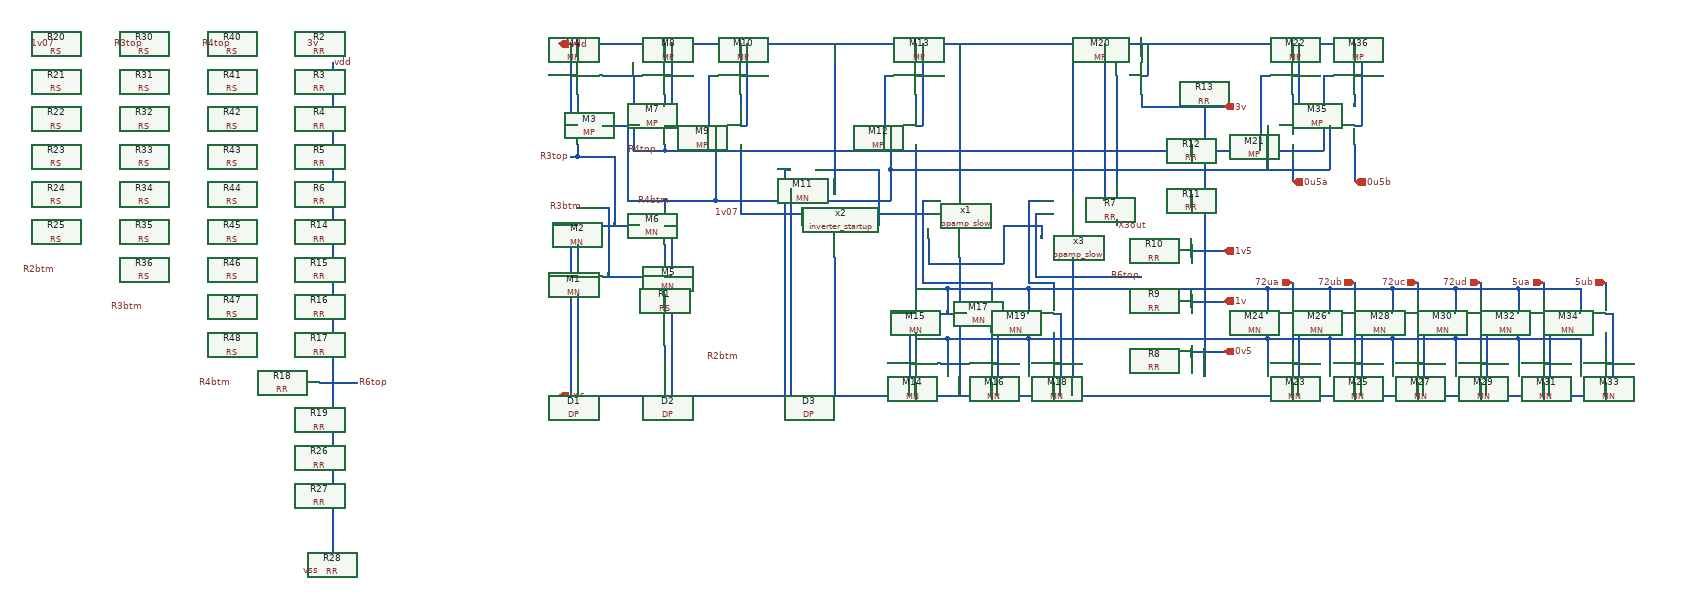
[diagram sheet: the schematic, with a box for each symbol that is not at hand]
v {xschem version=3.4.8RC file_version=1.3}
G {}
K {}
V {}
S {}
F {}
E {}
N 150 400 150 420 {lab=#net1}
N 50 370 110 370 {lab=R3btm}
N 50 290 110 290 {lab=R3top}
N 10 320 10 340 {lab=#net2}
N 150 320 150 340 {lab=#net3}
N 0 290 10 290 {lab=vss}
N 0 370 10 370 {lab=vss}
N 150 290 160 290 {lab=vss}
N 150 370 160 370 {lab=vss}
N 10 80 10 100 {lab=#net4}
N 150 80 150 100 {lab=#net5}
N 50 130 110 130 {lab=R4btm}
N 50 50 110 50 {lab=R4top}
N 0 50 10 50 {lab=vdd}
N 10 0 10 20 {lab=vdd}
N 150 0 150 20 {lab=vdd}
N 0 130 10 130 {lab=vdd}
N 150 130 160 130 {lab=vdd}
N 150 50 160 50 {lab=vdd}
N 100 50 100 170 {lab=R4top}
N 0 0 0 130 {lab=vdd}
N 160 0 160 130 {lab=vdd}
N 150 480 150 500 {lab=#net6}
N 0 290 0 560 {lab=vss}
N 10 400 10 500 {lab=#net7}
N 160 290 160 560 {lab=vss}
N 90 130 90 250 {lab=R4btm}
N 270 80 270 100 {lab=#net8}
N 270 0 270 20 {lab=vdd}
N 270 130 280 130 {lab=vdd}
N 270 50 280 50 {lab=vdd}
N 280 0 280 130 {lab=vdd}
N 220 50 220 170 {lab=R4top}
N 230 130 230 250 {lab=R4btm}
N 350 230 350 560 {lab=vss}
N 340 200 350 200 {lab=vss}
N 340 200 340 560 {lab=vss}
N 420 340 420 560 {lab=vss}
N 390 200 490 200 {lab=#net9}
N 490 200 490 290 {lab=#net9}
N 420 0 420 240 {lab=vdd}
N 550 80 550 100 {lab=#net10}
N 550 0 550 20 {lab=vdd}
N 550 130 560 130 {lab=vdd}
N 550 50 560 50 {lab=vdd}
N 560 0 560 130 {lab=vdd}
N 500 50 500 170 {lab=R4top}
N 540 430 550 430 {lab=vss}
N 540 510 550 510 {lab=vss}
N 550 460 550 480 {lab=#net11}
N 550 540 550 560 {lab=vss}
N 540 430 540 560 {lab=vss}
N 550 160 550 400 {lab=#net12}
N 670 430 680 430 {lab=vss}
N 670 510 680 510 {lab=vss}
N 670 460 670 480 {lab=#net13}
N 670 540 670 560 {lab=vss}
N 680 430 680 560 {lab=vss}
N 590 430 630 430 {lab=#net12}
N 590 510 630 510 {lab=#net11}
N 600 470 600 510 {lab=#net11}
N 600 390 600 430 {lab=#net12}
N 570 310 570 350 {lab=#net14}
N 690 290 690 350 {lab=#net14}
N 570 350 690 350 {lab=#net14}
N 620 340 620 560 {lab=vss}
N 620 0 620 240 {lab=vdd}
N 500 270 570 270 {lab=1v07}
N 560 250 570 250 {lab=#net15}
N 560 250 560 380 {lab=#net15}
N 560 380 670 380 {lab=#net15}
N 670 380 670 400 {lab=#net15}
N 270 270 500 270 {lab=1v07}
N 550 390 600 390 {lab=#net12}
N 550 470 600 470 {lab=#net11}
N 770 430 780 430 {lab=vss}
N 770 510 780 510 {lab=vss}
N 770 460 770 480 {lab=#net16}
N 770 540 770 560 {lab=vss}
N 780 430 780 560 {lab=vss}
N 770 380 770 400 {lab=#net17}
N 600 390 730 390 {lab=#net12}
N 730 390 730 430 {lab=#net12}
N 600 470 730 470 {lab=#net11}
N 730 470 730 510 {lab=#net11}
N 800 340 800 560 {lab=vss}
N 800 0 800 240 {lab=vdd}
N 690 290 750 290 {lab=#net14}
N 750 290 750 310 {lab=#net14}
N 730 250 750 250 {lab=#net17}
N 730 250 730 380 {lab=#net17}
N 730 380 770 380 {lab=#net17}
N 870 280 870 290 {lab=X3out}
N 740 270 750 270 {lab=R6top}
N 740 270 740 370 {lab=R6top}
N 910 50 920 50 {lab=vdd}
N 740 370 910 370 {lab=R6top}
N 1150 80 1150 100 {lab=#net18}
N 1150 0 1150 20 {lab=vdd}
N 1150 130 1160 130 {lab=vdd}
N 1150 50 1160 50 {lab=vdd}
N 1160 0 1160 130 {lab=vdd}
N 910 0 910 20 {lab=vdd}
N 870 50 870 220 {lab=#net19}
N 920 0 920 50 {lab=vdd}
N 910 100 990 100 {lab=3v}
N 990 160 990 180 {lab=#net20}
N 990 240 990 260 {lab=#net21}
N 990 320 990 340 {lab=1v5}
N 990 400 990 420 {lab=1v}
N 990 480 990 500 {lab=0v5}
N 1100 50 1100 170 {lab=R4top}
N 1110 130 1110 200 {lab=R4btm}
N 1150 430 1160 430 {lab=vss}
N 1150 510 1160 510 {lab=vss}
N 1150 460 1150 480 {lab=#net22}
N 1150 540 1150 560 {lab=vss}
N 1160 430 1160 560 {lab=vss}
N 1150 380 1150 400 {lab=72ua}
N 1110 390 1110 430 {lab=#net12}
N 1110 470 1110 510 {lab=#net11}
N 220 50 230 50 {lab=R4top}
N 500 50 510 50 {lab=R4top}
N 1100 50 1110 50 {lab=R4top}
N 1250 430 1260 430 {lab=vss}
N 1250 510 1260 510 {lab=vss}
N 1250 460 1250 480 {lab=#net23}
N 1250 540 1250 560 {lab=vss}
N 1260 430 1260 560 {lab=vss}
N 1250 380 1250 400 {lab=72ub}
N 1110 390 1210 390 {lab=#net12}
N 1210 390 1210 430 {lab=#net12}
N 1110 470 1210 470 {lab=#net11}
N 1210 470 1210 510 {lab=#net11}
N 1350 430 1360 430 {lab=vss}
N 1350 510 1360 510 {lab=vss}
N 1350 460 1350 480 {lab=#net24}
N 1350 540 1350 560 {lab=vss}
N 1360 430 1360 560 {lab=vss}
N 1350 380 1350 400 {lab=72uc}
N 1210 390 1310 390 {lab=#net12}
N 1310 390 1310 430 {lab=#net12}
N 1210 470 1310 470 {lab=#net11}
N 1310 470 1310 510 {lab=#net11}
N 1450 430 1460 430 {lab=vss}
N 1450 510 1460 510 {lab=vss}
N 1450 460 1450 480 {lab=#net25}
N 1450 540 1450 560 {lab=vss}
N 1460 430 1460 560 {lab=vss}
N 1450 380 1450 400 {lab=72ud}
N 1310 390 1410 390 {lab=#net12}
N 1410 390 1410 430 {lab=#net12}
N 1310 470 1410 470 {lab=#net11}
N 1410 470 1410 510 {lab=#net11}
N 1550 430 1560 430 {lab=vss}
N 1550 510 1560 510 {lab=vss}
N 1550 460 1550 480 {lab=#net26}
N 1550 540 1550 560 {lab=vss}
N 1560 430 1560 560 {lab=vss}
N 1550 380 1550 400 {lab=5ua}
N 1410 390 1510 390 {lab=#net12}
N 1510 390 1510 430 {lab=#net12}
N 1410 470 1510 470 {lab=#net11}
N 1510 470 1510 510 {lab=#net11}
N 1650 430 1660 430 {lab=vss}
N 1650 510 1660 510 {lab=vss}
N 1650 460 1650 480 {lab=#net27}
N 1650 540 1650 560 {lab=vss}
N 1660 430 1660 560 {lab=vss}
N 1650 380 1650 400 {lab=5ub}
N 1510 390 1610 390 {lab=#net12}
N 1610 390 1610 430 {lab=#net12}
N 1510 470 1610 470 {lab=#net11}
N 1610 470 1610 510 {lab=#net11}
N 1150 160 1150 220 {lab=0u5a}
N 1250 80 1250 100 {lab=#net28}
N 1250 0 1250 20 {lab=vdd}
N 1250 130 1260 130 {lab=vdd}
N 1250 50 1260 50 {lab=vdd}
N 1260 0 1260 130 {lab=vdd}
N 1200 50 1200 170 {lab=R4top}
N 1210 130 1210 200 {lab=R4btm}
N 1200 50 1210 50 {lab=R4top}
N 1250 160 1250 220 {lab=0u5b}
N 510 130 510 200 {lab=R4btm}
N 510 200 510 250 {lab=R4btm}
N 990 100 1040 100 {lab=3v}
N 990 330 1040 330 {lab=1v5}
N 990 410 1040 410 {lab=1v}
N 990 490 1040 490 {lab=0v5}
N -20 0 1260 -0 {lab=vdd}
N 100 170 150 170 {lab=R4top}
N 150 170 1200 170 {lab=R4top}
N 90 250 150 250 {lab=R4btm}
N 150 250 230 250 {lab=R4btm}
N 510 200 1210 200 {lab=R4btm}
N 230 250 510 250 {lab=R4btm}
N -20 560 1660 560 {lab=vss}
N 730 390 1110 390 {lab=#net12}
N 730 470 1110 470 {lab=#net11}
N 10 160 10 180 {lab=R3top}
N 70 180 70 290 {lab=R3top}
N 150 160 150 170 {lab=R4top}
N 10 260 60 260 {lab=R3btm}
N 60 260 60 370 {lab=R3btm}
N 150 250 150 260 {lab=R4btm}
N 370 270 370 290 {lab=1v07}
N 270 160 270 270 {lab=1v07}
N 10 180 70 180 {lab=R3top}
N 0 180 10 180 {lab=R3top}
N 850 0 850 250 {lab=vdd}
N 1010 100 1010 530 {lab=3v}
N -400 540 -340 540 {lab=R6top}
N -380 30 -380 810 {lab=vdd}
N 910 80 910 100 {lab=3v}
C {MN.sym} 50 370 0 1 {name=M1 model=NMOS w=10u l=2u nrd=0 nrs=0 m=5 spiceprefix=X}
C {MN.sym} 50 290 0 1 {name=M2 model=NMOS w=20u l=1u nrd=0 nrs=0 m=5 spiceprefix=X}
C {MN.sym} 110 370 0 0 {name=M5 model=NMOS w=10u l=2u nrd=0 nrs=0 m=5 spiceprefix=X}
C {MN.sym} 110 290 0 0 {name=M6 model=NMOS w=20u l=1u nrd=0 nrs=0 m=5 spiceprefix=X}
C {RS.sym} -680 0 0 0 {name=R30
w=4e-6
R=1
l=50e-6
model=F_RS
spiceprefix=X
tc1=0
tc2=0}
C {MP.sym} 50 130 0 1 {name=M3 model=PMOS w=20u l=1u nrd=0 nrs=0 m=5 spiceprefix=X}
C {MP.sym} 50 50 0 1 {name=M4 model=PMOS w=25u l=2u nrd=0 nrs=0 m=5 spiceprefix=X}
C {MP.sym} 110 130 0 0 {name=M7 model=PMOS w=20u l=1u nrd=0 nrs=0 m=5 spiceprefix=X}
C {MP.sym} 110 50 0 0 {name=M8 model=PMOS w=25u l=2u nrd=0 nrs=0 m=5 spiceprefix=X}
C {RS.sym} 150 420 0 0 {name=R1
w=4e-6
R=1
l=40.0e-6
model=F_RS
spiceprefix=X
tc1=0
tc2=0}
C {MP.sym} 230 130 0 0 {name=M9 model=PMOS w=20u l=1u nrd=0 nrs=0 m=5 spiceprefix=X}
C {MP.sym} 230 50 0 0 {name=M10 model=PMOS w=25u l=2u nrd=0 nrs=0 m=5 spiceprefix=X}
C {MN.sym} 390 200 0 1 {name=M11 model=NMOS w=10u l=2u nrd=0 nrs=0 m=3 spiceprefix=X}
C {inverter_startup.sym} 390 290 0 0 {name=x2}
C {MP.sym} 510 130 0 0 {name=M12 model=PMOS w=20u l=1u nrd=0 nrs=0 m=5 spiceprefix=X}
C {MP.sym} 510 50 0 0 {name=M13 model=PMOS w=25u l=2u nrd=0 nrs=0 m=5 spiceprefix=X}
C {MN.sym} 590 510 0 1 {name=M14 model=NMOS w=10u l=2u nrd=0 nrs=0 m=5 spiceprefix=X}
C {MN.sym} 590 430 0 1 {name=M15 model=NMOS w=20u l=1u nrd=0 nrs=0 m=5 spiceprefix=X}
C {MN.sym} 630 510 0 0 {name=M16 model=NMOS w=7u l=2u nrd=0 nrs=0 m=1 spiceprefix=X}
C {MN.sym} 630 430 0 0 {name=M17 model=NMOS w=15u l=1u nrd=0 nrs=0 m=1 spiceprefix=X}
C {opamp_slow.sym} 590 290 0 0 {name=x1}
C {MN.sym} 730 510 0 0 {name=M18 model=NMOS w=7u l=2u nrd=0 nrs=0 m=1 spiceprefix=X}
C {MN.sym} 730 430 0 0 {name=M19 model=NMOS w=15u l=1u nrd=0 nrs=0 m=1 spiceprefix=X}
C {opamp_slow.sym} 770 290 0 0 {name=x3}
C {MP.sym} 870 50 0 0 {name=M20 model=PMOS w=20u l=1u nrd=0 nrs=0 m=5 spiceprefix=X}
C {RR.sym} 870 280 2 0 {name=R7
w=2.8e-06
R=1
l=30.0e-06
model=F_RR
spiceprefix=X
tc1=0
tc2=0}
C {MP.sym} 1110 130 0 0 {name=M21 model=PMOS w=4u l=2u nrd=0 nrs=0 m=1 spiceprefix=X}
C {MP.sym} 1110 50 0 0 {name=M22 model=PMOS w=5u l=4u nrd=0 nrs=0 m=1 spiceprefix=X}
C {RR.sym} 990 500 0 0 {name=R8
w=2.8e-06
R=1
l=50.0e-06
model=F_RR
spiceprefix=X
tc1=0
tc2=0}
C {RR.sym} 990 340 0 0 {name=R10
w=2.8e-06
R=1
l=50.0e-06
model=F_RR
spiceprefix=X
tc1=0
tc2=0}
C {RR.sym} 990 260 0 0 {name=R11
w=2.8e-06
R=1
l=50.0e-06
model=F_RR
spiceprefix=X
tc1=0
tc2=0}
C {RR.sym} 990 180 0 0 {name=R12
w=2.8e-06
R=1
l=50.0e-06
model=F_RR
spiceprefix=X
tc1=0
tc2=0}
C {RR.sym} 990 100 0 0 {name=R13
w=2.8e-06
R=1
l=50.0e-06
model=F_RR
spiceprefix=X
tc1=0
tc2=0}
C {RR.sym} 990 420 0 0 {name=R9
w=2.8e-06
R=1
l=50.0e-06
model=F_RR
spiceprefix=X
tc1=0
tc2=0}
C {MN.sym} 1110 510 0 0 {name=M23 model=NMOS w=10u l=2u nrd=0 nrs=0 m=9 spiceprefix=X}
C {MN.sym} 1110 430 0 0 {name=M24 model=NMOS w=20u l=1u nrd=0 nrs=0 m=9 spiceprefix=X}
C {devices/iopin.sym} -20 0 0 1 {name=p2 lab=vdd}
C {devices/iopin.sym} -20 560 0 1 {name=p5 lab=vss}
C {devices/opin.sym} 1040 490 0 0 {name=p6 lab=0v5}
C {devices/opin.sym} 1040 330 0 0 {name=p3 lab=1v5}
C {devices/opin.sym} 1040 410 0 0 {name=p4 lab=1v}
C {devices/opin.sym} 1040 100 0 0 {name=p1 lab=3v}
C {MN.sym} 1210 510 0 0 {name=M25 model=NMOS w=10u l=2u nrd=0 nrs=0 m=9 spiceprefix=X}
C {MN.sym} 1210 430 0 0 {name=M26 model=NMOS w=20u l=1u nrd=0 nrs=0 m=9 spiceprefix=X}
C {devices/opin.sym} 1150 220 1 0 {name=p7 lab=0u5a}
C {devices/ipin.sym} 1150 380 1 0 {name=p8 lab=72ua}
C {devices/ipin.sym} 1250 380 1 0 {name=p9 lab=72ub}
C {MN.sym} 1310 510 0 0 {name=M27 model=NMOS w=10u l=2u nrd=0 nrs=0 m=9 spiceprefix=X}
C {MN.sym} 1310 430 0 0 {name=M28 model=NMOS w=20u l=1u nrd=0 nrs=0 m=9 spiceprefix=X}
C {devices/ipin.sym} 1350 380 1 0 {name=p10 lab=72uc}
C {MN.sym} 1410 510 0 0 {name=M29 model=NMOS w=10u l=2u nrd=0 nrs=0 m=9 spiceprefix=X}
C {MN.sym} 1410 430 0 0 {name=M30 model=NMOS w=20u l=1u nrd=0 nrs=0 m=9 spiceprefix=X}
C {devices/ipin.sym} 1450 380 1 0 {name=p11 lab=72ud}
C {MN.sym} 1510 510 0 0 {name=M31 model=NMOS w=7u l=2u nrd=0 nrs=0 m=1 spiceprefix=X}
C {MN.sym} 1510 430 0 0 {name=M32 model=NMOS w=15u l=1u nrd=0 nrs=0 m=1 spiceprefix=X}
C {devices/ipin.sym} 1550 380 1 0 {name=p12 lab=5ua}
C {MN.sym} 1610 510 0 0 {name=M33 model=NMOS w=7u l=2u nrd=0 nrs=0 m=1 spiceprefix=X}
C {MN.sym} 1610 430 0 0 {name=M34 model=NMOS w=15u l=1u nrd=0 nrs=0 m=1 spiceprefix=X}
C {devices/ipin.sym} 1650 380 1 0 {name=p13 lab=5ub}
C {MP.sym} 1210 130 0 0 {name=M35 model=PMOS w=4u l=2u nrd=0 nrs=0 m=1 spiceprefix=X}
C {MP.sym} 1210 50 0 0 {name=M36 model=PMOS w=5u l=4u nrd=0 nrs=0 m=1 spiceprefix=X}
C {devices/opin.sym} 1250 220 1 0 {name=p14 lab=0u5b}
C {devices/lab_pin.sym} 270 270 0 0 {name=p17 sig_type=std_logic lab=1v07}
C {IP62LIB/DP.sym} 10 560 2 0 {name=D1
model=DP
w=3.6u
l=3.6u
a="expr_eng( @w * @l )"
p="expr_eng( 2 * ( @w + @l ) )"
spiceprefix=D
m=1}
C {IP62LIB/DP.sym} 150 560 2 0 {name=D2
model=DP
w=3.6u
l=3.6u
a="expr_eng( @w * @l )"
p="expr_eng( 2 * ( @w + @l ) )"
spiceprefix=D
m=4}
C {IP62LIB/DP.sym} 270 560 2 0 {name=D3
model=DP
w=3.6u
l=3.6u
a="expr_eng( @w * @l )"
p="expr_eng( 2 * ( @w + @l ) )"
spiceprefix=D
m=1}
C {RS.sym} -680 60 0 0 {name=R31
w=4e-6
R=1
l=50e-6
model=F_RS
spiceprefix=X
tc1=0
tc2=0}
C {RS.sym} -680 120 0 0 {name=R32
w=4e-6
R=1
l=50e-6
model=F_RS
spiceprefix=X
tc1=0
tc2=0}
C {RS.sym} -680 180 0 0 {name=R33
w=4e-6
R=1
l=50e-6
model=F_RS
spiceprefix=X
tc1=0
tc2=0}
C {RS.sym} -680 240 0 0 {name=R34
w=4e-6
R=1
l=50e-6
model=F_RS
spiceprefix=X
tc1=0
tc2=0}
C {RS.sym} -680 300 0 0 {name=R35
w=4e-6
R=1
l=50e-6
model=F_RS
spiceprefix=X
tc1=0
tc2=0}
C {RS.sym} -680 360 0 0 {name=R36
w=4e-6
R=1
l=50e-6
model=F_RS
spiceprefix=X
tc1=0
tc2=0}
C {RS.sym} -540 0 0 0 {name=R40
w=4e-6
R=1
l=50e-6
model=F_RS
spiceprefix=X
tc1=0
tc2=0}
C {RS.sym} -540 60 0 0 {name=R41
w=4e-6
R=1
l=50e-6
model=F_RS
spiceprefix=X
tc1=0
tc2=0}
C {RS.sym} -540 120 0 0 {name=R42
w=4e-6
R=1
l=50e-6
model=F_RS
spiceprefix=X
tc1=0
tc2=0}
C {RS.sym} -540 180 0 0 {name=R43
w=4e-6
R=1
l=50e-6
model=F_RS
spiceprefix=X
tc1=0
tc2=0}
C {RS.sym} -540 240 0 0 {name=R44
w=4e-6
R=1
l=50e-6
model=F_RS
spiceprefix=X
tc1=0
tc2=0}
C {RS.sym} -540 420 0 0 {name=R47
w=4e-6
R=1
l=50e-6
model=F_RS
spiceprefix=X
tc1=0
tc2=0}
C {RS.sym} -540 480 0 0 {name=R48
w=4e-6
R=1
l=50e-6
model=F_RS
spiceprefix=X
tc1=0
tc2=0}
C {RS.sym} -820 0 0 0 {name=R20
w=4e-6
R=1
l=40.0e-6
model=F_RS
spiceprefix=X
tc1=0
tc2=0}
C {RS.sym} -820 60 0 0 {name=R21
w=4e-6
R=1
l=40.0e-6
model=F_RS
spiceprefix=X
tc1=0
tc2=0}
C {RS.sym} -820 120 0 0 {name=R22
w=4e-6
R=1
l=40.0e-6
model=F_RS
spiceprefix=X
tc1=0
tc2=0}
C {RS.sym} -820 180 0 0 {name=R23
w=4e-6
R=1
l=40.0e-6
model=F_RS
spiceprefix=X
tc1=0
tc2=0}
C {RS.sym} -820 300 0 0 {name=R25
w=4e-6
R=1
l=40.0e-6
model=F_RS
spiceprefix=X
tc1=0
tc2=0}
C {RS.sym} -820 240 0 0 {name=R24
w=4e-6
R=1
l=40.0e-6
model=F_RS
spiceprefix=X
tc1=0
tc2=0}
C {TR-1umLIB/RR.sym} -400 0 0 0 {name=R2
w=2.8e-06
R=1
l=30e-06
model=F_RR
spiceprefix=X
tc1=0
tc2=0
m=1}
C {TR-1umLIB/RR.sym} -400 60 0 0 {name=R3
w=2.8e-06
R=1
l=30e-06
model=F_RR
spiceprefix=X
tc1=0
tc2=0
m=1}
C {TR-1umLIB/RR.sym} -400 120 0 0 {name=R4
w=2.8e-06
R=1
l=30e-06
model=F_RR
spiceprefix=X
tc1=0
tc2=0
m=1}
C {TR-1umLIB/RR.sym} -400 180 0 0 {name=R5
w=2.8e-06
R=1
l=30e-06
model=F_RR
spiceprefix=X
tc1=0
tc2=0
m=1}
C {TR-1umLIB/RR.sym} -400 360 0 0 {name=R15
w=2.8e-06
R=1
l=30e-06
model=F_RR
spiceprefix=X
tc1=0
tc2=0
m=1}
C {TR-1umLIB/RR.sym} -400 420 0 0 {name=R16
w=2.8e-06
R=1
l=30e-06
model=F_RR
spiceprefix=X
tc1=0
tc2=0
m=1}
C {TR-1umLIB/RR.sym} -400 480 0 0 {name=R17
w=2.8e-06
R=1
l=30e-06
model=F_RR
spiceprefix=X
tc1=0
tc2=0
m=1}
C {TR-1umLIB/RR.sym} -400 540 0 0 {name=R18
w=2.8e-06
R=1
l=30e-06
model=F_RR
spiceprefix=X
tc1=0
tc2=0
m=1}
C {TR-1umLIB/RR.sym} -400 600 0 0 {name=R19
w=2.8e-06
R=1
l=30e-06
model=F_RR
spiceprefix=X
tc1=0
tc2=0
m=1}
C {TR-1umLIB/RR.sym} -400 660 0 0 {name=R26
w=2.8e-06
R=1
l=30e-06
model=F_RR
spiceprefix=X
tc1=0
tc2=0
m=1}
C {TR-1umLIB/RR.sym} -400 720 0 0 {name=R27
w=2.8e-06
R=1
l=30e-06
model=F_RR
spiceprefix=X
tc1=0
tc2=0
m=1}
C {TR-1umLIB/RR.sym} -400 780 0 0 {name=R28
w=2.8e-06
R=1
l=30e-06
model=F_RR
spiceprefix=X
tc1=0
tc2=0
m=1}
C {devices/lab_pin.sym} -540 0 0 0 {name=p15 sig_type=std_logic lab=R4top}
C {devices/lab_pin.sym} 140 170 3 0 {name=p16 sig_type=std_logic lab=R4top}
C {devices/lab_pin.sym} -540 540 0 0 {name=p18 sig_type=std_logic lab=R4btm}
C {devices/lab_pin.sym} 160 250 1 0 {name=p19 sig_type=std_logic lab=R4btm}
C {devices/lab_pin.sym} -680 0 0 0 {name=p20 sig_type=std_logic lab=R3top}
C {devices/lab_pin.sym} -680 420 0 0 {name=p21 sig_type=std_logic lab=R3btm}
C {devices/lab_pin.sym} 0 180 3 0 {name=p22 sig_type=std_logic lab=R3top}
C {devices/lab_pin.sym} 20 260 1 0 {name=p23 sig_type=std_logic lab=R3btm}
C {devices/lab_pin.sym} -400 0 0 0 {name=p24 sig_type=std_logic lab=3v}
C {devices/lab_pin.sym} -820 0 0 0 {name=p25 sig_type=std_logic lab=1v07}
C {devices/lab_pin.sym} -820 360 0 0 {name=p26 sig_type=std_logic lab=R2btm}
C {devices/lab_pin.sym} 270 500 1 0 {name=p27 sig_type=std_logic lab=R2btm}
C {devices/lab_pin.sym} -340 540 0 1 {name=p29 sig_type=std_logic lab=R6top}
C {devices/lab_pin.sym} -400 840 0 0 {name=p30 sig_type=std_logic lab=vss}
C {devices/lab_pin.sym} -380 30 0 1 {name=p31 sig_type=std_logic lab=vdd}
C {devices/lab_pin.sym} 910 370 3 1 {name=p32 sig_type=std_logic lab=R6top}
C {TR-1umLIB/RS.sym} -540 300 0 0 {name=R45
w=4e-6
R=1
l=50e-6
model=F_RS
spiceprefix=X
tc1=0
tc2=0
m=1}
C {TR-1umLIB/RS.sym} -540 360 0 0 {name=R46
w=4e-6
R=1
l=50e-6
model=F_RS
spiceprefix=X
tc1=0
tc2=0
m=1}
C {TR-1umLIB/RR.sym} -400 240 0 0 {name=R6
w=2.8e-06
R=1
l=30e-06
model=F_RR
spiceprefix=X
tc1=0
tc2=0
m=1}
C {TR-1umLIB/RR.sym} -400 300 0 0 {name=R14
w=2.8e-06
R=1
l=30e-06
model=F_RR
spiceprefix=X
tc1=0
tc2=0
m=1}
C {devices/lab_pin.sym} 870 290 0 1 {name=p28 sig_type=std_logic lab=X3out}
